VERSION 5.7 ;
  NOWIREEXTENSIONATPIN ON ;
  DIVIDERCHAR "/" ;
  BUSBITCHARS "[]" ;
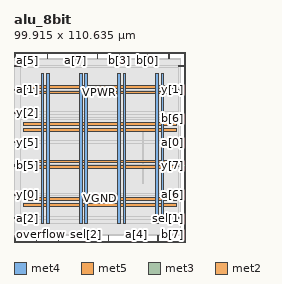
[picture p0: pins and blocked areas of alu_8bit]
MACRO alu_8bit
  CLASS BLOCK ;
  FOREIGN alu_8bit ;
  ORIGIN 0.000 0.000 ;
  SIZE 99.915 BY 110.635 ;
  PIN VGND
    DIRECTION INOUT ;
    USE GROUND ;
    PORT
      LAYER met4 ;
        RECT 19.115 10.640 20.715 98.160 ;
    END
    PORT
      LAYER met4 ;
        RECT 41.310 10.640 42.910 98.160 ;
    END
    PORT
      LAYER met4 ;
        RECT 63.505 10.640 65.105 98.160 ;
    END
    PORT
      LAYER met4 ;
        RECT 85.700 10.640 87.300 98.160 ;
    END
    PORT
      LAYER met5 ;
        RECT 5.280 24.260 94.540 25.860 ;
    END
    PORT
      LAYER met5 ;
        RECT 5.280 46.020 94.540 47.620 ;
    END
    PORT
      LAYER met5 ;
        RECT 5.280 67.780 94.540 69.380 ;
    END
    PORT
      LAYER met5 ;
        RECT 5.280 89.540 94.540 91.140 ;
    END
  END VGND
  PIN VPWR
    DIRECTION INOUT ;
    USE POWER ;
    PORT
      LAYER met4 ;
        RECT 15.815 10.640 17.415 98.160 ;
    END
    PORT
      LAYER met4 ;
        RECT 38.010 10.640 39.610 98.160 ;
    END
    PORT
      LAYER met4 ;
        RECT 60.205 10.640 61.805 98.160 ;
    END
    PORT
      LAYER met4 ;
        RECT 82.400 10.640 84.000 98.160 ;
    END
    PORT
      LAYER met5 ;
        RECT 5.280 20.960 94.540 22.560 ;
    END
    PORT
      LAYER met5 ;
        RECT 5.280 42.720 94.540 44.320 ;
    END
    PORT
      LAYER met5 ;
        RECT 5.280 64.480 94.540 66.080 ;
    END
    PORT
      LAYER met5 ;
        RECT 5.280 86.240 94.540 87.840 ;
    END
  END VPWR
  PIN a[0]
    DIRECTION INPUT ;
    USE SIGNAL ;
    ANTENNAGATEAREA 0.213000 ;
    PORT
      LAYER met3 ;
        RECT 95.915 57.840 99.915 58.440 ;
    END
  END a[0]
  PIN a[1]
    DIRECTION INPUT ;
    USE SIGNAL ;
    ANTENNAGATEAREA 0.213000 ;
    PORT
      LAYER met3 ;
        RECT 0.000 88.440 4.000 89.040 ;
    END
  END a[1]
  PIN a[2]
    DIRECTION INPUT ;
    USE SIGNAL ;
    ANTENNAGATEAREA 0.213000 ;
    PORT
      LAYER met3 ;
        RECT 0.000 13.640 4.000 14.240 ;
    END
  END a[2]
  PIN a[3]
    DIRECTION INPUT ;
    USE SIGNAL ;
    ANTENNAGATEAREA 0.742500 ;
    PORT
      LAYER met2 ;
        RECT 19.410 106.635 19.690 110.635 ;
    END
  END a[3]
  PIN a[4]
    DIRECTION INPUT ;
    USE SIGNAL ;
    ANTENNAGATEAREA 0.495000 ;
    PORT
      LAYER met2 ;
        RECT 70.930 0.000 71.210 4.000 ;
    END
  END a[4]
  PIN a[5]
    DIRECTION INPUT ;
    USE SIGNAL ;
    ANTENNAGATEAREA 0.213000 ;
    PORT
      LAYER met2 ;
        RECT 6.530 106.635 6.810 110.635 ;
    END
  END a[5]
  PIN a[6]
    DIRECTION INPUT ;
    USE SIGNAL ;
    ANTENNAGATEAREA 0.213000 ;
    PORT
      LAYER met3 ;
        RECT 95.915 27.240 99.915 27.840 ;
    END
  END a[6]
  PIN a[7]
    DIRECTION INPUT ;
    USE SIGNAL ;
    ANTENNAGATEAREA 0.159000 ;
    PORT
      LAYER met2 ;
        RECT 35.510 106.635 35.790 110.635 ;
    END
  END a[7]
  PIN b[0]
    DIRECTION INPUT ;
    USE SIGNAL ;
    ANTENNAGATEAREA 0.213000 ;
    PORT
      LAYER met2 ;
        RECT 77.370 106.635 77.650 110.635 ;
    END
  END b[0]
  PIN b[1]
    DIRECTION INPUT ;
    USE SIGNAL ;
    ANTENNAGATEAREA 0.247500 ;
    PORT
      LAYER met2 ;
        RECT 83.810 0.000 84.090 4.000 ;
    END
  END b[1]
  PIN b[2]
    DIRECTION INPUT ;
    USE SIGNAL ;
    ANTENNAGATEAREA 0.196500 ;
    PORT
      LAYER met3 ;
        RECT 95.915 102.040 99.915 102.640 ;
    END
  END b[2]
  PIN b[3]
    DIRECTION INPUT ;
    USE SIGNAL ;
    ANTENNAGATEAREA 0.196500 ;
    PORT
      LAYER met2 ;
        RECT 61.270 106.635 61.550 110.635 ;
    END
  END b[3]
  PIN b[4]
    DIRECTION INPUT ;
    USE SIGNAL ;
    ANTENNAGATEAREA 0.196500 ;
    PORT
      LAYER met2 ;
        RECT 90.250 106.635 90.530 110.635 ;
    END
  END b[4]
  PIN b[5]
    DIRECTION INPUT ;
    USE SIGNAL ;
    ANTENNAGATEAREA 0.196500 ;
    PORT
      LAYER met3 ;
        RECT 0.000 44.240 4.000 44.840 ;
    END
  END b[5]
  PIN b[6]
    DIRECTION INPUT ;
    USE SIGNAL ;
    ANTENNAGATEAREA 0.213000 ;
    PORT
      LAYER met3 ;
        RECT 95.915 71.440 99.915 72.040 ;
    END
  END b[6]
  PIN b[7]
    DIRECTION INPUT ;
    USE SIGNAL ;
    ANTENNAGATEAREA 0.213000 ;
    PORT
      LAYER met2 ;
        RECT 96.690 0.000 96.970 4.000 ;
    END
  END b[7]
  PIN carry
    DIRECTION OUTPUT TRISTATE ;
    USE SIGNAL ;
    PORT
      LAYER met2 ;
        RECT 0.090 0.000 0.370 4.000 ;
    END
  END carry
  PIN overflow
    DIRECTION OUTPUT TRISTATE ;
    USE SIGNAL ;
    PORT
      LAYER met2 ;
        RECT 12.970 0.000 13.250 4.000 ;
    END
  END overflow
  PIN sel[0]
    DIRECTION INPUT ;
    USE SIGNAL ;
    ANTENNAGATEAREA 0.213000 ;
    PORT
      LAYER met2 ;
        RECT 25.850 0.000 26.130 4.000 ;
    END
  END sel[0]
  PIN sel[1]
    DIRECTION INPUT ;
    USE SIGNAL ;
    ANTENNAGATEAREA 0.196500 ;
    PORT
      LAYER met3 ;
        RECT 95.915 13.640 99.915 14.240 ;
    END
  END sel[1]
  PIN sel[2]
    DIRECTION INPUT ;
    USE SIGNAL ;
    ANTENNAGATEAREA 0.159000 ;
    PORT
      LAYER met2 ;
        RECT 41.950 0.000 42.230 4.000 ;
    END
  END sel[2]
  PIN y[0]
    DIRECTION OUTPUT TRISTATE ;
    USE SIGNAL ;
    ANTENNADIFFAREA 0.795200 ;
    PORT
      LAYER met3 ;
        RECT 0.000 27.240 4.000 27.840 ;
    END
  END y[0]
  PIN y[1]
    DIRECTION OUTPUT TRISTATE ;
    USE SIGNAL ;
    ANTENNADIFFAREA 0.795200 ;
    PORT
      LAYER met3 ;
        RECT 95.915 88.440 99.915 89.040 ;
    END
  END y[1]
  PIN y[2]
    DIRECTION OUTPUT TRISTATE ;
    USE SIGNAL ;
    ANTENNADIFFAREA 0.795200 ;
    PORT
      LAYER met3 ;
        RECT 0.000 74.840 4.000 75.440 ;
    END
  END y[2]
  PIN y[3]
    DIRECTION OUTPUT TRISTATE ;
    USE SIGNAL ;
    ANTENNADIFFAREA 0.795200 ;
    PORT
      LAYER met2 ;
        RECT 48.390 106.635 48.670 110.635 ;
    END
  END y[3]
  PIN y[4]
    DIRECTION OUTPUT TRISTATE ;
    USE SIGNAL ;
    ANTENNADIFFAREA 0.795200 ;
    PORT
      LAYER met2 ;
        RECT 54.830 0.000 55.110 4.000 ;
    END
  END y[4]
  PIN y[5]
    DIRECTION OUTPUT TRISTATE ;
    USE SIGNAL ;
    ANTENNADIFFAREA 0.795200 ;
    PORT
      LAYER met3 ;
        RECT 0.000 57.840 4.000 58.440 ;
    END
  END y[5]
  PIN y[6]
    DIRECTION OUTPUT TRISTATE ;
    USE SIGNAL ;
    ANTENNADIFFAREA 0.795200 ;
    PORT
      LAYER met3 ;
        RECT 0.000 102.040 4.000 102.640 ;
    END
  END y[6]
  PIN y[7]
    DIRECTION OUTPUT TRISTATE ;
    USE SIGNAL ;
    ANTENNADIFFAREA 1.336500 ;
    PORT
      LAYER met3 ;
        RECT 95.915 44.240 99.915 44.840 ;
    END
  END y[7]
  OBS
      LAYER li1 ;
        RECT 5.520 10.795 94.300 98.005 ;
      LAYER met1 ;
        RECT 0.070 10.640 96.990 98.160 ;
      LAYER met2 ;
        RECT 0.100 106.355 6.250 106.635 ;
        RECT 7.090 106.355 19.130 106.635 ;
        RECT 19.970 106.355 35.230 106.635 ;
        RECT 36.070 106.355 48.110 106.635 ;
        RECT 48.950 106.355 60.990 106.635 ;
        RECT 61.830 106.355 77.090 106.635 ;
        RECT 77.930 106.355 89.970 106.635 ;
        RECT 90.810 106.355 96.960 106.635 ;
        RECT 0.100 4.280 96.960 106.355 ;
        RECT 0.650 3.670 12.690 4.280 ;
        RECT 13.530 3.670 25.570 4.280 ;
        RECT 26.410 3.670 41.670 4.280 ;
        RECT 42.510 3.670 54.550 4.280 ;
        RECT 55.390 3.670 70.650 4.280 ;
        RECT 71.490 3.670 83.530 4.280 ;
        RECT 84.370 3.670 96.410 4.280 ;
      LAYER met3 ;
        RECT 4.400 101.640 95.515 102.505 ;
        RECT 3.990 89.440 95.915 101.640 ;
        RECT 4.400 88.040 95.515 89.440 ;
        RECT 3.990 75.840 95.915 88.040 ;
        RECT 4.400 74.440 95.915 75.840 ;
        RECT 3.990 72.440 95.915 74.440 ;
        RECT 3.990 71.040 95.515 72.440 ;
        RECT 3.990 58.840 95.915 71.040 ;
        RECT 4.400 57.440 95.515 58.840 ;
        RECT 3.990 45.240 95.915 57.440 ;
        RECT 4.400 43.840 95.515 45.240 ;
        RECT 3.990 28.240 95.915 43.840 ;
        RECT 4.400 26.840 95.515 28.240 ;
        RECT 3.990 14.640 95.915 26.840 ;
        RECT 4.400 13.240 95.515 14.640 ;
        RECT 3.990 10.715 95.915 13.240 ;
      LAYER met4 ;
        RECT 74.815 34.175 75.145 64.425 ;
  END
END alu_8bit
END LIBRARY

